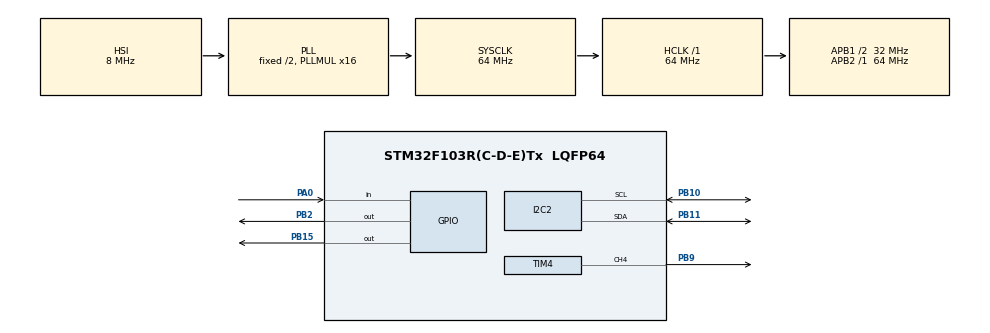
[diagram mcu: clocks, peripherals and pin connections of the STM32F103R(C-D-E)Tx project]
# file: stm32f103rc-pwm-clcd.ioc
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Mcu.Family=STM32F1
Mcu.Name=STM32F103R(C-D-E)Tx
Mcu.Package=LQFP64
NVIC.PriorityGroup=NVIC_PRIORITYGROUP_4
NVIC.RTC_IRQn=true\:0\:0\:false\:false\:true\:true\:true
NVIC.TIM4_IRQn=true\:0\:0\:false\:false\:true\:true\:true
NVIC.TIM6_IRQn=true\:0\:0\:false\:false\:true\:true\:true
NVIC.TIM7_IRQn=true\:0\:0\:false\:false\:true\:false\:true
NVIC.TimeBase=TIM7_IRQn
NVIC.TimeBaseIP=TIM7
PA0-WKUP.Signal=GPIO_Input
PA13.Mode=Serial_Wire
PA13.Signal=SYS_JTMS-SWDIO
PA14.Mode=Serial_Wire
PA14.Signal=SYS_JTCK-SWCLK
PB10.Mode=I2C
PB10.Signal=I2C2_SCL
PB11.Mode=I2C
PB11.Signal=I2C2_SDA
PB15.Signal=GPIO_Output
PB2.Signal=GPIO_Output
PB9.Signal=S_TIM4_CH4
ProjectManager.HeapSize=0x200
ProjectManager.StackSize=0x400
ProjectManager.TargetToolchain=MDK-ARM V5
RCC.AHBFreq_Value=64000000
RCC.APB1CLKDivider=RCC_HCLK_DIV2
RCC.APB1Freq_Value=32000000
RCC.APB1TimFreq_Value=64000000
RCC.APB2Freq_Value=64000000
RCC.APB2TimFreq_Value=64000000
RCC.HCLKFreq_Value=64000000
RCC.PLLMUL=RCC_PLL_MUL16
RCC.SYSCLKFreq_VALUE=64000000
RCC.SYSCLKSource=RCC_SYSCLKSOURCE_PLLCLK
RCC.USBFreq_Value=64000000
RTC.AutoPrediv=RTC_AUTO_1_SECOND
RTC.Date=25
RTC.Format=RTC_FORMAT_BIN
RTC.Hours=11
RTC.Minutes=59
RTC.Month=RTC_MONTH_MAY
RTC.Seconds=50
SH.S_TIM4_CH4.0=TIM4_CH4,PWM Generation4 CH4
TIM4.AutoReloadPreload=TIM_AUTORELOAD_PRELOAD_DISABLE
TIM4.Channel-PWM\ Generation4\ CH4=TIM_CHANNEL_4
TIM4.Period=99
TIM4.Prescaler=6399
TIM4.Pulse-PWM\ Generation4\ CH4=49
VP_RTC_VS_RTC_Activate.Mode=RTC_Enabled
VP_RTC_VS_RTC_Calendar.Mode=RTC_Calendar
VP_SYS_VS_tim7.Mode=TIM7
VP_TIM4_VS_ClockSourceINT.Mode=Internal
VP_TIM6_VS_ClockSourceINT.Mode=Enable_Timer
board=custom

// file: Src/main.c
/* USER CODE BEGIN Header */
/**
  ******************************************************************************
  * @file           : main.c
  * @brief          : Main program body
  ******************************************************************************
  * @attention
  *
  * <h2><center>&copy; Copyright (c) 2019 STMicroelectronics.
  * All rights reserved.</center></h2>
  *
  * This software component is licensed by ST under BSD 3-Clause license,
  * the "License"; You may not use this file except in compliance with the
  * License. You may obtain a copy of the License at:
  *                        opensource.org/licenses/BSD-3-Clause
  *
  ******************************************************************************
  */
/* USER CODE END Header */

#include "main.h"
#include "STM_HAL_CLCD.h"
#include "stdio.h"

I2C_HandleTypeDef hi2c2;

RTC_HandleTypeDef hrtc;

TIM_HandleTypeDef htim4;
TIM_HandleTypeDef htim6;

void SystemClock_Config(void);
static void MX_GPIO_Init(void);
static void MX_I2C2_Init(void);
static void MX_RTC_Init(void);
static void MX_TIM4_Init(void);
static void MX_TIM6_Init(void);

  Clcd_TypeDef CLCD = {
        {GPIOC, GPIO_PIN_5},   //RS
        {GPIOC, GPIO_PIN_4},   //EN
        {GPIOC, GPIO_PIN_3},   //D4
        {GPIOC, GPIO_PIN_2},   //D5
        {GPIOC, GPIO_PIN_1},   //D6
        {GPIOC, GPIO_PIN_0},   //D7
      };

int main(void)
{
  char buf[16];
	uint8_t i=0;
	uint8_t ii=20;
	uint32_t j,jj;

  HAL_Init();

  SystemClock_Config();

  MX_GPIO_Init();
  MX_I2C2_Init();
  MX_RTC_Init();
  MX_TIM4_Init();
  MX_TIM6_Init();

  RTC_TimeTypeDef tTime = {0};
	HAL_TIM_Base_Start_IT (&htim6);
	HAL_TIM_Base_Start_IT (&htim4);
  HAL_TIM_PWM_Start (&htim4,TIM_CHANNEL_4);

	Clcd_Init(&CLCD);
	//Clcd_Cursor_Mode(&CLCD,1);
	//Clcd_Blink_Mode(&CLCD,1);
	//Clcd_Shift_Mode(&CLCD,2);

  while (1)
  {
    while(ii!=0) ii--;
		jj= RCC->CFGR;

		HAL_RTC_GetTime(&hrtc, &tTime, RTC_FORMAT_BIN);
		sprintf(buf,"%d:%d:%d",tTime.Hours,tTime.Minutes,tTime.Seconds);
		Clcd_Clear(&CLCD);
		Clcd_Gotoxy(&CLCD,0,0);
		Clcd_Write_String(&CLCD,buf);
		if(HAL_GPIO_ReadPin(GPIOA,GPIO_PIN_0))  HAL_TIM_Base_Start_IT (&htim6);
		else HAL_TIM_Base_Stop_IT(&htim6);
		i++;
		if(i==1)	j=HAL_RCC_GetSysClockFreq();
		else if(i==2) j=HAL_RCC_GetHCLKFreq();
		else if(i==3) j=HAL_RCC_GetPCLK1Freq();
		else if(i==4) j=HAL_RCC_GetPCLK2Freq();
		else i=0;
		sprintf(buf,"N=%d,F=%d",i,j);
	//	sprintf(buf,"%d",jj);
		Clcd_Gotoxy(&CLCD,1,0);
		Clcd_Write_String(&CLCD,buf);
		HAL_Delay(1500);

  }

}

void SystemClock_Config(void)
{
  RCC_OscInitTypeDef RCC_OscInitStruct = {0};
  RCC_ClkInitTypeDef RCC_ClkInitStruct = {0};
  RCC_PeriphCLKInitTypeDef PeriphClkInit = {0};

  /** Initializes the CPU, AHB and APB busses clocks
  */
  RCC_OscInitStruct.OscillatorType = RCC_OSCILLATORTYPE_HSI|RCC_OSCILLATORTYPE_LSI;
  RCC_OscInitStruct.HSIState = RCC_HSI_ON;
  RCC_OscInitStruct.HSICalibrationValue = RCC_HSICALIBRATION_DEFAULT;
  RCC_OscInitStruct.LSIState = RCC_LSI_ON;
  RCC_OscInitStruct.PLL.PLLState = RCC_PLL_ON;
  RCC_OscInitStruct.PLL.PLLSource = RCC_PLLSOURCE_HSI_DIV2;
  RCC_OscInitStruct.PLL.PLLMUL = RCC_PLL_MUL16;
  if (HAL_RCC_OscConfig(&RCC_OscInitStruct) != HAL_OK)
  {
    Error_Handler();
  }
  /** Initializes the CPU, AHB and APB busses clocks
  */
  RCC_ClkInitStruct.ClockType = RCC_CLOCKTYPE_HCLK|RCC_CLOCKTYPE_SYSCLK
                              |RCC_CLOCKTYPE_PCLK1|RCC_CLOCKTYPE_PCLK2;
  RCC_ClkInitStruct.SYSCLKSource = RCC_SYSCLKSOURCE_PLLCLK;
  RCC_ClkInitStruct.AHBCLKDivider = RCC_SYSCLK_DIV1;
  RCC_ClkInitStruct.APB1CLKDivider = RCC_HCLK_DIV2;
  RCC_ClkInitStruct.APB2CLKDivider = RCC_HCLK_DIV1;

  if (HAL_RCC_ClockConfig(&RCC_ClkInitStruct, FLASH_LATENCY_2) != HAL_OK)
  {
    Error_Handler();
  }
  PeriphClkInit.PeriphClockSelection = RCC_PERIPHCLK_RTC;
  PeriphClkInit.RTCClockSelection = RCC_RTCCLKSOURCE_LSI;
  if (HAL_RCCEx_PeriphCLKConfig(&PeriphClkInit) != HAL_OK)
  {
    Error_Handler();
  }

}

static void MX_I2C2_Init(void)
{

  hi2c2.Instance = I2C2;
  hi2c2.Init.ClockSpeed = 100000;
  hi2c2.Init.DutyCycle = I2C_DUTYCYCLE_2;
  hi2c2.Init.OwnAddress1 = 0;
  hi2c2.Init.AddressingMode = I2C_ADDRESSINGMODE_7BIT;
  hi2c2.Init.DualAddressMode = I2C_DUALADDRESS_DISABLE;
  hi2c2.Init.OwnAddress2 = 0;
  hi2c2.Init.GeneralCallMode = I2C_GENERALCALL_DISABLE;
  hi2c2.Init.NoStretchMode = I2C_NOSTRETCH_DISABLE;
  if (HAL_I2C_Init(&hi2c2) != HAL_OK)
  {
    Error_Handler();
  }

}

static void MX_RTC_Init(void)
{

  RTC_TimeTypeDef sTime = {0};
  RTC_DateTypeDef DateToUpdate = {0};

  /** Initialize RTC Only
  */
  hrtc.Instance = RTC;
  hrtc.Init.AsynchPrediv = RTC_AUTO_1_SECOND;
  hrtc.Init.OutPut = RTC_OUTPUTSOURCE_ALARM;
  if (HAL_RTC_Init(&hrtc) != HAL_OK)
  {
    Error_Handler();
  }

  /** Initialize RTC and set the Time and Date
  */
  sTime.Hours = 11;
  sTime.Minutes = 59;
  sTime.Seconds = 50;

  if (HAL_RTC_SetTime(&hrtc, &sTime, RTC_FORMAT_BIN) != HAL_OK)
  {
    Error_Handler();
  }
  DateToUpdate.WeekDay = RTC_WEEKDAY_MONDAY;
  DateToUpdate.Month = RTC_MONTH_MAY;
  DateToUpdate.Date = 25;
  DateToUpdate.Year = 0;

  if (HAL_RTC_SetDate(&hrtc, &DateToUpdate, RTC_FORMAT_BIN) != HAL_OK)
  {
    Error_Handler();
  }

}

static void MX_TIM4_Init(void)
{

  TIM_ClockConfigTypeDef sClockSourceConfig = {0};
  TIM_MasterConfigTypeDef sMasterConfig = {0};
  TIM_OC_InitTypeDef sConfigOC = {0};

  htim4.Instance = TIM4;
  htim4.Init.Prescaler =5999;
  htim4.Init.CounterMode = TIM_COUNTERMODE_UP;
  htim4.Init.Period =99;
  htim4.Init.ClockDivision = TIM_CLOCKDIVISION_DIV1;
  htim4.Init.AutoReloadPreload = TIM_AUTORELOAD_PRELOAD_DISABLE;
  if (HAL_TIM_Base_Init(&htim4) != HAL_OK)
  {
    Error_Handler();
  }
  sClockSourceConfig.ClockSource = TIM_CLOCKSOURCE_INTERNAL;
  if (HAL_TIM_ConfigClockSource(&htim4, &sClockSourceConfig) != HAL_OK)
  {
    Error_Handler();
  }
  if (HAL_TIM_PWM_Init(&htim4) != HAL_OK)
  {
    Error_Handler();
  }
  sMasterConfig.MasterOutputTrigger = TIM_TRGO_RESET;
  sMasterConfig.MasterSlaveMode = TIM_MASTERSLAVEMODE_DISABLE;
  if (HAL_TIMEx_MasterConfigSynchronization(&htim4, &sMasterConfig) != HAL_OK)
  {
    Error_Handler();
  }
  sConfigOC.OCMode = TIM_OCMODE_PWM1;
  sConfigOC.Pulse = 49;
  sConfigOC.OCPolarity = TIM_OCPOLARITY_HIGH;
  sConfigOC.OCFastMode = TIM_OCFAST_DISABLE;
  if (HAL_TIM_PWM_ConfigChannel(&htim4, &sConfigOC, TIM_CHANNEL_4) != HAL_OK)
  {
    Error_Handler();
  }
  HAL_TIM_MspPostInit(&htim4);

}

static void MX_TIM6_Init(void)
{

  TIM_MasterConfigTypeDef sMasterConfig = {0};

  htim6.Instance = TIM6;
  htim6.Init.Prescaler = 5999;
  htim6.Init.CounterMode = TIM_COUNTERMODE_UP;
  htim6.Init.Period = 9999;
  htim6.Init.AutoReloadPreload = TIM_AUTORELOAD_PRELOAD_DISABLE;
  if (HAL_TIM_Base_Init(&htim6) != HAL_OK)
  {
    Error_Handler();
  }
  sMasterConfig.MasterOutputTrigger = TIM_TRGO_RESET;
  sMasterConfig.MasterSlaveMode = TIM_MASTERSLAVEMODE_DISABLE;
  if (HAL_TIMEx_MasterConfigSynchronization(&htim6, &sMasterConfig) != HAL_OK)
  {
    Error_Handler();
  }

}

static void MX_GPIO_Init(void)
{
  GPIO_InitTypeDef GPIO_InitStruct = {0};

  /* GPIO Ports Clock Enable */
  __HAL_RCC_GPIOA_CLK_ENABLE();
  __HAL_RCC_GPIOB_CLK_ENABLE();
  __HAL_RCC_GPIOC_CLK_ENABLE();

  /*Configure GPIO pin Output Level */
  HAL_GPIO_WritePin(GPIOB, GPIO_PIN_2|GPIO_PIN_15, GPIO_PIN_RESET);
  HAL_GPIO_WritePin(GPIOC, GPIO_PIN_0|GPIO_PIN_1|GPIO_PIN_2|GPIO_PIN_3|GPIO_PIN_4|GPIO_PIN_5, GPIO_PIN_RESET);
  /*Configure GPIO pin : PA0 */
  GPIO_InitStruct.Pin = GPIO_PIN_0;
  GPIO_InitStruct.Mode = GPIO_MODE_INPUT;
  GPIO_InitStruct.Pull = GPIO_PULLUP;
  HAL_GPIO_Init(GPIOA, &GPIO_InitStruct);

  /*Configure GPIO pins : PB2 PB15 */
  GPIO_InitStruct.Pin = GPIO_PIN_2|GPIO_PIN_15;
  GPIO_InitStruct.Mode = GPIO_MODE_OUTPUT_PP;
  GPIO_InitStruct.Pull = GPIO_NOPULL;
  GPIO_InitStruct.Speed = GPIO_SPEED_FREQ_MEDIUM;
  HAL_GPIO_Init(GPIOB, &GPIO_InitStruct);

	GPIO_InitStruct.Pin = GPIO_PIN_0|GPIO_PIN_1|GPIO_PIN_2|GPIO_PIN_3|GPIO_PIN_4|GPIO_PIN_5;
  GPIO_InitStruct.Mode = GPIO_MODE_OUTPUT_PP;
  GPIO_InitStruct.Pull = GPIO_NOPULL;
  GPIO_InitStruct.Speed = GPIO_SPEED_FREQ_MEDIUM;
  HAL_GPIO_Init(GPIOC, &GPIO_InitStruct);

}

void HAL_TIM_PeriodElapsedCallback(TIM_HandleTypeDef *htim)
{
   static uint16_t ti2,coun;

  if (htim->Instance == TIM7) {
    HAL_IncTick();
  }
  	if (htim->Instance == TIM6) {
    HAL_GPIO_TogglePin(GPIOB,GPIO_PIN_2);
  }
	if (htim->Instance == TIM4) {
	 coun++;
	 if(coun>99) coun=0;
	 if(coun<50) ti2=coun;
   else   ti2=99-coun;
   //TIM2->CCR2=ti2*2;
	 TIM4->CCR4=ti2*2;}
}

void Error_Handler(void)
{
}

/************************ (C) COPYRIGHT STMicroelectronics *****END OF FILE****/
